! (c) 2009  Infineon Technologies AG, Munich
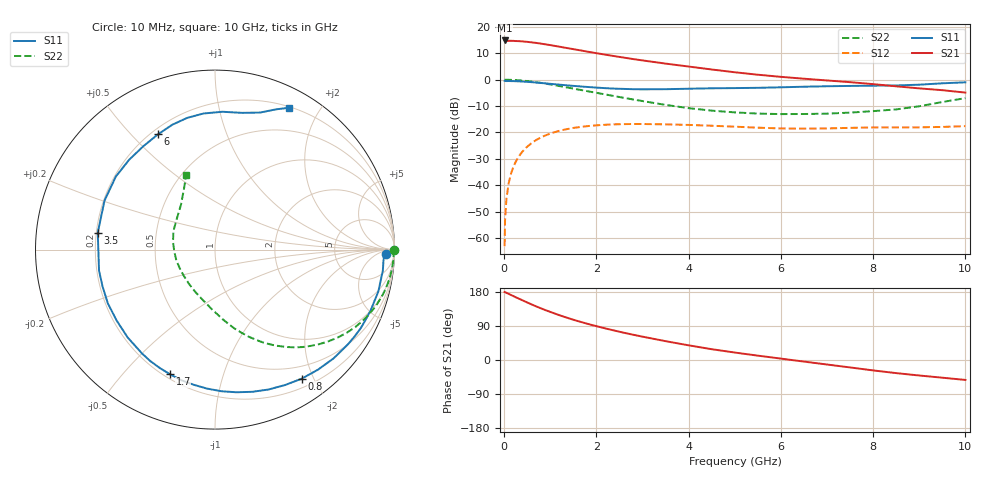
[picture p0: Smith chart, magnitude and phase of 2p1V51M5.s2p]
! Infineon Technologies  Discrete & RF Semiconductors
! BFP420
! VCE =  1.5 V,  IC =  1.5 mA
! Common Emitter S-Parameters:  Nov 2009
# GHz  S  MA  R  50
!  f  S11  S21  S12  S22
! GHz  MAG  ANG  MAG  ANG  MAG  ANG  MAG  ANG
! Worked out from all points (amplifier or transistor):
!   46 points, 10 MHz to 10 GHz, reference 50 ohm
!   highest |S21| = 14.9 dB at 10 MHz (marker M1)
!   |S21| within 3 dB of that: start of sweep to 1.404 GHz
!   unconditionally stable (mu >= 1): 4.128 GHz to end of sweep
!   at 300 MHz: K = 0.03, MSG = 22.1 dB, |S12| = -29.6 dB
!   at 1.7 GHz: K = 0.32, MSG = 14.4 dB, |S12| = -17.8 dB
!   at 10 GHz: K = 1.26, MAG = 3.3 dB, |S12| = -17.6 dB
!   lowest NFmin = 0.52 dB at 900 MHz
!   S11 on the Smith chart (normalised r, x): 10 MHz: 32, -16; 800 MHz: 0.32, -1.84; 1.7 GHz: 0.22, -0.68; 3.5 GHz: 0.21, +0.07; 6 GHz: 0.23, +0.60; 10 GHz: 0.21, +1.63
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0.01  0.9515 -1.4  5.533 179.4  0.0007 95.8  0.9951 -0.1
0.02  0.9437 -1.5  5.38 179.2  0.0022 88.4  0.9956 -0.8
0.05  0.9406 -3.8  5.422 177.2  0.0056 87.8  0.9956 -2.1
0.15  0.939 -10.6  5.448 171.5  0.0167 83.9  0.9913 -6.5
0.35  0.9259 -25.0  5.349 160.2  0.0384 75.3  0.9681 -15.0
0.5  0.9095 -35.5  5.207 151.8  0.0538 69.0  0.94 -21.1
0.7  0.8812 -49.4  4.966 141.2  0.0723 60.8  0.8931 -28.9
0.8  0.8666 -56.0  4.811 136.2  0.0806 57.0  0.867 -32.4
1  0.8345 -69.1  4.517 126.9  0.0953 49.8  0.8115 -39.1
1.2  0.8037 -81.5  4.211 118.1  0.1075 43.2  0.7562 -45.2
1.5  0.7623 -99.0  3.786 106.3  0.1217 34.4  0.6772 -53.3
1.7  0.7381 -109.9  3.532 99.2  0.1287 29.1  0.6289 -58.1
2.2  0.6902 -134.8  2.973 83.2  0.1399 17.7  0.5237 -68.5
2.6  0.668 -153.3  2.614 71.8  0.1439 9.8  0.452 -76.2
3  0.6567 -169.7  2.316 61.6  0.1445 3.2  0.3932 -83.3
3.5  0.6599 171.8  2.016 49.7  0.1423 -3.7  0.3329 -93.0
4.5  0.6862 143.6  1.559 28.5  0.134 -13.5  0.2589 -115.6
5.5  0.7008 124.7  1.241 11.5  0.1231 -18.5  0.2278 -138.9
6  0.7166 116.3  1.131 3.7  0.1191 -19.2  0.2226 -151.7
7  0.7502 101.9  0.966 -11.9  0.1192 -19.5  0.2271 -177.2
8.5  0.7766 78.8  0.748 -34.6  0.1246 -24.2  0.2732 141.3
10  0.8907 62.5  0.569 -52.6  0.1317 -26.2  0.4468 111.0
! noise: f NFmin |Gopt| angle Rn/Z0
0.9  0.52  0.55  33  0.27
1.8  1.07  0.35  77  0.21
2.4  1.18  0.36  101  0.18
3  1.41  0.36  134  0.13
4  1.68  0.4  -172  0.1
5  2.08  0.44  -130  0.32
6  2.89  0.57  -114  0.39
